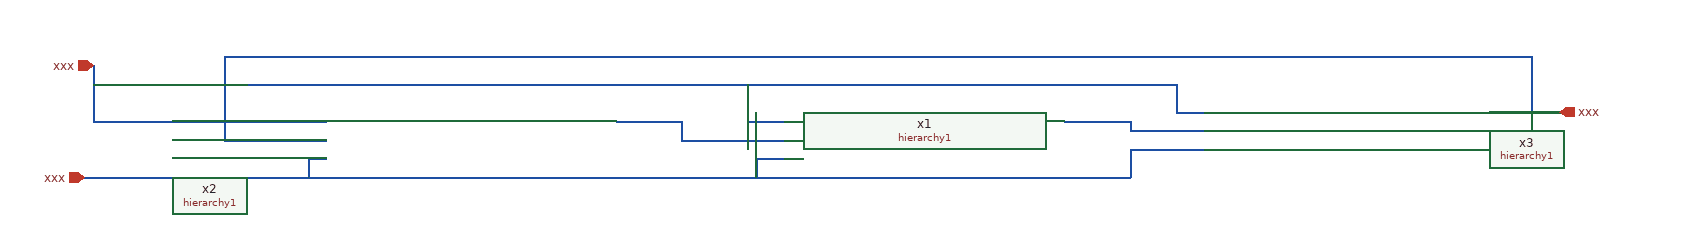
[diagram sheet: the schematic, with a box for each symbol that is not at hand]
v {xschem version=3.4.6RC file_version=1.2
}
G {}
K {}
V {}
S {}
E {}
N -670 -150 -670 -90 {lab=xxx}
N -670 -90 -420 -90 {lab=xxx}
N 820 -100 910 -100 {lab=xxx}
N -110 -90 -40 -90 {lab=#net1}
N -40 -90 -40 -70 {lab=#net1}
N -40 -70 70 -70 {lab=#net1}
N 370 -90 440 -90 {lab=#net2}
N 440 -90 440 -80 {lab=#net2}
N 440 -80 520 -80 {lab=#net2}
N -530 -70 -420 -70 {lab=xxx}
N -530 -160 -530 -70 {lab=xxx}
N -530 -160 870 -160 {lab=xxx}
N 870 -160 870 -100 {lab=xxx}
N 440 -60 520 -60 {lab=xxx}
N 440 -60 440 -30 {lab=xxx}
N -680 -30 440 -30 {lab=xxx}
N -440 -50 -420 -50 {lab=xxx}
N -440 -50 -440 -30 {lab=xxx}
N 40 -50 70 -50 {lab=xxx}
N 40 -50 40 -30 {lab=xxx}
N 490 -100 520 -100 {lab=xxx}
N 490 -130 490 -100 {lab=xxx}
N -670 -130 490 -130 {lab=xxx}
N 30 -90 70 -90 {lab=xxx}
N 30 -130 30 -90 {lab=xxx}
C {hierarchy1.sym} 220 -70 0 0 {name=x1}
C {hierarchy1.sym} -270 -70 0 0 {name=x2}
C {hierarchy1.sym} 670 -80 0 0 {name=x3}
C {devices/iopin.sym} -670 -150 2 0 {name=p1 lab=xxx}
C {devices/iopin.sym} -680 -30 2 0 {name=p2 lab=xxx}
C {devices/opin.sym} 900 -100 0 0 {name=p3 lab=xxx}
